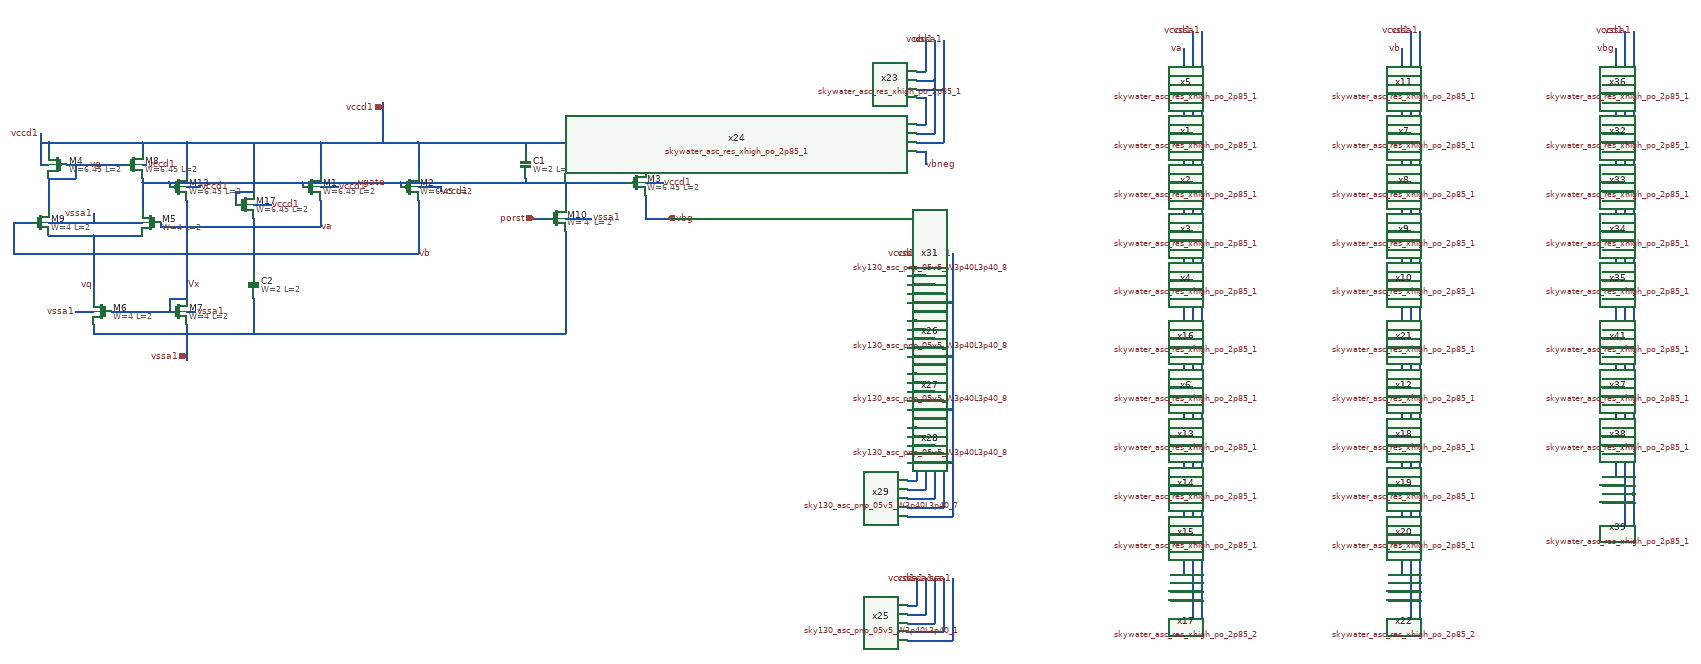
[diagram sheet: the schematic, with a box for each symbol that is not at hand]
v {xschem version=3.0.0 file_version=1.2 }
G {}
K {}
V {}
S {}
E {}
N 2040 520 2260 520 { lab=vccd1}
N 2260 520 2460 520 { lab=vccd1}
N 1430 600 1490 600 { lab=vg}
N 1490 570 1490 600 { lab=vg}
N 1470 570 1490 570 { lab=vg}
N 1490 570 1600 570 { lab=vg}
N 1430 520 1430 540 { lab=vccd1}
N 1430 600 1430 670 { lab=vg}
N 1640 610 1640 670 { lab=vgate}
N 1630 730 1640 730 { lab=vq}
N 1640 570 1650 570 { lab=vccd1}
N 1420 570 1430 570 { lab=vccd1}
N 1430 700 1440 700 { lab=vssa1}
N 1630 700 1640 700 { lab=vssa1}
N 1520 900 1530 900 { lab=vssa1}
N 1570 900 1700 900 { lab=Vx}
N 1740 900 1750 900 { lab=vssa1}
N 1700 870 1700 900 { lab=Vx}
N 1700 870 1740 870 { lab=Vx}
N 2650 520 2770 520 { lab=vccd1}
N 2260 520 2260 590 { lab=vccd1}
N 2770 610 2780 610 { lab=vccd1}
N 2220 610 2220 620 { lab=vgate}
N 2000 610 2000 620 { lab=vgate}
N 1740 620 1750 620 { lab=vccd1}
N 2040 620 2050 620 { lab=vccd1}
N 2040 520 2040 590 { lab=vccd1}
N 2260 620 2270 620 { lab=vccd1}
N 1780 520 2040 520 { lab=vccd1}
N 2700 610 2730 610 { lab=vgate}
N 1700 610 1700 620 { lab=vgate}
N 1740 520 1740 590 { lab=vccd1}
N 1910 710 2040 710 { lab=va}
N 2770 520 2770 580 { lab=vccd1}
N 1430 520 1640 520 { lab=vccd1}
N 1430 730 1440 730 { lab=vq}
N 1530 730 1630 730 { lab=vq}
N 2460 520 2650 520 { lab=vccd1}
N 1740 650 1740 840 { lab=Vx}
N 2000 610 2220 610 { lab=vgate}
N 2220 610 2700 610 { lab=vgate}
N 1440 730 1530 730 { lab=vq}
N 1640 600 1640 610 { lab=vgate}
N 1640 610 1700 610 { lab=vgate}
N 1640 520 1740 520 { lab=vccd1}
N 1440 700 1630 700 { lab=vssa1}
N 1740 520 1780 520 { lab=vccd1}
N 1840 610 2000 610 { lab=vgate}
N 1700 610 1840 610 { lab=vgate}
N 2590 690 2600 690 { lab=vssa1}
N 2590 610 2590 660 { lab=vgate}
N 2500 520 2500 540 { lab=vccd1}
N 2500 600 2500 610 { lab=vgate}
N 1830 710 1910 710 { lab=va}
N 1370 770 2150 770 { lab=#net1}
N 2040 650 2040 710 { lab=va}
N 1680 710 1830 710 { lab=va}
N 1680 700 1680 710 { lab=va}
N 1890 690 1890 710 { lab=va}
N 1850 630 1890 630 { lab=vccd1}
N 1850 630 1850 660 { lab=vccd1}
N 1890 520 1890 630 { lab=vccd1}
N 2770 690 2830 690 { lab=vbg}
N 2150 770 2260 770 { lab=#net1}
N 2180 450 2180 520 { lab=vccd1}
N 2780 610 2810 610 { lab=vccd1}
N 2310 620 2310 630 { lab=vccd1}
N 2270 620 2310 620 { lab=vccd1}
N 2050 620 2080 620 { lab=vccd1}
N 1750 620 1770 620 { lab=vccd1}
N 1640 520 1640 540 { lab=vccd1}
N 1410 570 1420 570 { lab=vccd1}
N 1410 500 1410 570 { lab=vccd1}
N 2600 690 2650 690 { lab=vssa1}
N 1890 660 1930 660 { lab=vccd1}
N 2510 690 2550 690 { lab=porst}
N 1750 900 1760 900 { lab=vssa1}
N 1490 900 1520 900 { lab=vssa1}
N 1530 680 1530 700 { lab=vssa1}
N 1350 700 1390 700 { lab=#net1}
N 1350 700 1350 770 { lab=#net1}
N 1350 770 1370 770 { lab=#net1}
N 2180 430 2180 450 { lab=vccd1}
N 3950 430 3980 430 { lab=#net2}
N 3980 430 3980 480 { lab=#net2}
N 3950 480 3980 480 { lab=#net2}
N 3950 540 3980 540 { lab=#net3}
N 3980 540 3980 590 { lab=#net3}
N 3950 590 3980 590 { lab=#net3}
N 3950 650 3980 650 { lab=#net4}
N 3980 650 3980 700 { lab=#net4}
N 3950 700 3980 700 { lab=#net4}
N 3950 760 3980 760 { lab=#net5}
N 3980 760 3980 810 { lab=#net5}
N 3950 810 3980 810 { lab=#net5}
N 3950 870 3980 870 { lab=#net6}
N 3980 870 3980 920 { lab=#net6}
N 3950 1000 3980 1000 { lab=#net7}
N 3980 1000 3980 1050 { lab=#net7}
N 3950 1050 3980 1050 { lab=#net7}
N 3950 1110 3980 1110 { lab=#net8}
N 3980 1110 3980 1160 { lab=#net8}
N 3950 1160 3980 1160 { lab=#net8}
N 3950 1220 3980 1220 { lab=#net9}
N 3980 1220 3980 1270 { lab=#net9}
N 3950 1270 3980 1270 { lab=#net9}
N 3950 1330 3980 1330 { lab=#net10}
N 3980 1330 3980 1380 { lab=#net10}
N 3950 1380 3980 1380 { lab=#net10}
N 3950 1440 3980 1440 { lab=#net11}
N 3950 940 3980 940 { lab=#net6}
N 3980 920 3980 940 { lab=#net6}
N 3950 1490 3980 1490 { lab=#net11}
N 3980 1440 3980 1490 { lab=#net11}
N 3950 370 3980 370 { lab=va}
N 3980 310 3980 370 { lab=va}
N 3950 390 4000 390 { lab=vccd1}
N 4000 390 4000 1510 { lab=vccd1}
N 3950 1510 4000 1510 { lab=vccd1}
N 3950 500 4000 500 { lab=vccd1}
N 3950 610 4000 610 { lab=vccd1}
N 3950 720 4000 720 { lab=vccd1}
N 3950 830 4000 830 { lab=vccd1}
N 3950 960 4000 960 { lab=vccd1}
N 3950 1070 4000 1070 { lab=vccd1}
N 3950 1180 4000 1180 { lab=vccd1}
N 3950 1290 4000 1290 { lab=vccd1}
N 3950 1400 4000 1400 { lab=vccd1}
N 4000 310 4000 390 { lab=vccd1}
N 4020 310 4020 1590 { lab=vssa1}
N 4000 1510 4000 1590 { lab=vccd1}
N 3950 1420 4020 1420 { lab=vssa1}
N 3950 1310 4020 1310 { lab=vssa1}
N 3950 1200 4020 1200 { lab=vssa1}
N 3950 980 4020 980 { lab=vssa1}
N 3950 850 4020 850 { lab=vssa1}
N 3950 740 4020 740 { lab=vssa1}
N 3950 630 4020 630 { lab=vssa1}
N 3950 520 4020 520 { lab=vssa1}
N 3950 410 4020 410 { lab=vssa1}
N 4000 270 4000 310 { lab=vccd1}
N 3950 1550 4020 1550 { lab=vssa1}
N 4020 270 4020 310 { lab=vssa1}
N 4440 430 4470 430 { lab=#net12}
N 4470 430 4470 480 { lab=#net12}
N 4440 480 4470 480 { lab=#net12}
N 4440 540 4470 540 { lab=#net13}
N 4470 540 4470 590 { lab=#net13}
N 4440 590 4470 590 { lab=#net13}
N 4440 650 4470 650 { lab=#net14}
N 4470 650 4470 700 { lab=#net14}
N 4440 700 4470 700 { lab=#net14}
N 4440 760 4470 760 { lab=#net15}
N 4470 760 4470 810 { lab=#net15}
N 4440 810 4470 810 { lab=#net15}
N 4440 870 4470 870 { lab=#net16}
N 4470 870 4470 920 { lab=#net16}
N 4440 1000 4470 1000 { lab=#net17}
N 4470 1000 4470 1050 { lab=#net17}
N 4440 1050 4470 1050 { lab=#net17}
N 4440 1110 4470 1110 { lab=#net18}
N 4470 1110 4470 1160 { lab=#net18}
N 4440 1160 4470 1160 { lab=#net18}
N 4440 1220 4470 1220 { lab=#net19}
N 4470 1220 4470 1270 { lab=#net19}
N 4440 1270 4470 1270 { lab=#net19}
N 4440 1330 4470 1330 { lab=#net20}
N 4470 1330 4470 1380 { lab=#net20}
N 4440 1380 4470 1380 { lab=#net20}
N 4440 1440 4470 1440 { lab=#net21}
N 4440 940 4470 940 { lab=#net16}
N 4470 920 4470 940 { lab=#net16}
N 4440 1490 4470 1490 { lab=#net21}
N 4470 1440 4470 1490 { lab=#net21}
N 4440 370 4470 370 { lab=vb}
N 4470 310 4470 370 { lab=vb}
N 4440 390 4490 390 { lab=vccd1}
N 4490 390 4490 1510 { lab=vccd1}
N 4440 1510 4490 1510 { lab=vccd1}
N 4440 500 4490 500 { lab=vccd1}
N 4440 610 4490 610 { lab=vccd1}
N 4440 720 4490 720 { lab=vccd1}
N 4440 830 4490 830 { lab=vccd1}
N 4440 960 4490 960 { lab=vccd1}
N 4440 1070 4490 1070 { lab=vccd1}
N 4440 1180 4490 1180 { lab=vccd1}
N 4440 1290 4490 1290 { lab=vccd1}
N 4440 1400 4490 1400 { lab=vccd1}
N 4490 310 4490 390 { lab=vccd1}
N 4510 310 4510 1590 { lab=vssa1}
N 4490 1510 4490 1590 { lab=vccd1}
N 4440 1420 4510 1420 { lab=vssa1}
N 4440 1310 4510 1310 { lab=vssa1}
N 4440 1200 4510 1200 { lab=vssa1}
N 4440 980 4510 980 { lab=vssa1}
N 4440 850 4510 850 { lab=vssa1}
N 4440 740 4510 740 { lab=vssa1}
N 4440 630 4510 630 { lab=vssa1}
N 4440 520 4510 520 { lab=vssa1}
N 4440 410 4510 410 { lab=vssa1}
N 4490 270 4490 310 { lab=vccd1}
N 4440 1550 4510 1550 { lab=vssa1}
N 4510 270 4510 310 { lab=vssa1}
N 4920 430 4950 430 { lab=#net22}
N 4950 430 4950 480 { lab=#net22}
N 4920 480 4950 480 { lab=#net22}
N 4920 540 4950 540 { lab=#net23}
N 4950 540 4950 590 { lab=#net23}
N 4920 590 4950 590 { lab=#net23}
N 4920 650 4950 650 { lab=#net24}
N 4950 650 4950 700 { lab=#net24}
N 4920 700 4950 700 { lab=#net24}
N 4920 760 4950 760 { lab=#net25}
N 4950 760 4950 810 { lab=#net25}
N 4920 810 4950 810 { lab=#net25}
N 4920 870 4950 870 { lab=#net26}
N 4950 870 4950 920 { lab=#net26}
N 4920 1000 4950 1000 { lab=#net27}
N 4950 1000 4950 1050 { lab=#net27}
N 4920 1050 4950 1050 { lab=#net27}
N 4920 1110 4950 1110 { lab=#net28}
N 4950 1110 4950 1160 { lab=#net28}
N 4920 1160 4950 1160 { lab=#net28}
N 4920 1220 4950 1220 { lab=#net29}
N 4950 1220 4950 1270 { lab=#net29}
N 4920 1270 4950 1270 { lab=#net29}
N 4920 1330 4950 1330 { lab=vssa1}
N 4920 940 4950 940 { lab=#net26}
N 4950 920 4950 940 { lab=#net26}
N 4920 370 4950 370 { lab=vbg}
N 4950 310 4950 370 { lab=vbg}
N 4920 390 4970 390 { lab=vccd1}
N 4920 500 4970 500 { lab=vccd1}
N 4920 610 4970 610 { lab=vccd1}
N 4920 720 4970 720 { lab=vccd1}
N 4920 830 4970 830 { lab=vccd1}
N 4920 960 4970 960 { lab=vccd1}
N 4920 1070 4970 1070 { lab=vccd1}
N 4920 1180 4970 1180 { lab=vccd1}
N 4920 1290 4970 1290 { lab=vccd1}
N 4970 310 4970 390 { lab=vccd1}
N 4920 1310 4990 1310 { lab=vssa1}
N 4920 1200 4990 1200 { lab=vssa1}
N 4920 980 4990 980 { lab=vssa1}
N 4920 850 4990 850 { lab=vssa1}
N 4920 740 4990 740 { lab=vssa1}
N 4920 630 4990 630 { lab=vssa1}
N 4920 520 4990 520 { lab=vssa1}
N 4920 410 4990 410 { lab=vssa1}
N 4970 270 4970 310 { lab=vccd1}
N 4990 270 4990 310 { lab=vssa1}
N 4990 310 4990 1310 { lab=vssa1}
N 4970 390 4970 1380 { lab=vccd1}
N 4990 1310 4990 1380 { lab=vssa1}
N 4950 1330 4990 1330 { lab=vssa1}
N 2770 640 2770 690 { lab=vbg}
N 3380 420 3400 420 { lab=#net30}
N 3400 420 3400 480 { lab=#net30}
N 3380 480 3400 480 { lab=#net30}
N 3400 290 3400 360 { lab=vb}
N 3380 360 3400 360 { lab=vb}
N 3400 540 3400 570 { lab=vbneg}
N 3380 540 3400 540 { lab=vbneg}
N 3380 380 3420 380 { lab=vccd1}
N 3420 380 3420 500 { lab=vccd1}
N 3380 500 3420 500 { lab=vccd1}
N 3380 520 3440 520 { lab=vssa1}
N 3440 400 3440 520 { lab=vssa1}
N 3380 400 3440 400 { lab=vssa1}
N 3420 290 3420 380 { lab=vccd1}
N 3440 290 3440 400 { lab=vssa1}
N 2260 650 2260 740 { lab=#net1}
N 3380 770 3380 1280 { lab=vccd1}
N 3360 1280 3380 1280 { lab=vccd1}
N 3400 770 3400 1300 { lab=vssa1}
N 3360 1300 3400 1300 { lab=vssa1}
N 3420 770 3420 1320 { lab=vssa1}
N 3360 1320 3420 1320 { lab=vssa1}
N 3440 770 3440 1340 { lab=vbneg}
N 3360 1340 3440 1340 { lab=vbneg}
N 3460 770 3460 1360 { lab=vssa1}
N 3360 1360 3460 1360 { lab=vssa1}
N 3360 800 3380 800 { lab=vccd1}
N 3360 820 3400 820 { lab=vssa1}
N 3360 840 3420 840 { lab=vssa1}
N 3360 860 3440 860 { lab=vbneg}
N 3360 880 3460 880 { lab=vssa1}
N 3360 920 3380 920 { lab=vccd1}
N 3360 940 3400 940 { lab=vssa1}
N 3360 960 3420 960 { lab=vssa1}
N 3360 980 3440 980 { lab=vbneg}
N 3360 1000 3460 1000 { lab=vssa1}
N 3360 1040 3380 1040 { lab=vccd1}
N 3360 1060 3400 1060 { lab=vssa1}
N 3360 1080 3420 1080 { lab=vssa1}
N 3360 1100 3440 1100 { lab=vbneg}
N 3360 1120 3460 1120 { lab=vssa1}
N 3360 1160 3380 1160 { lab=vccd1}
N 3360 1180 3400 1180 { lab=vssa1}
N 3360 1200 3420 1200 { lab=vssa1}
N 3360 1220 3440 1220 { lab=vbneg}
N 3360 1240 3460 1240 { lab=vssa1}
N 1740 950 1740 1010 { lab=vssa1}
N 3360 1620 3440 1620 { lab=va}
N 3440 1500 3440 1620 { lab=va}
N 3380 1500 3380 1560 { lab=vccd1}
N 3360 1560 3380 1560 { lab=vccd1}
N 3400 1500 3400 1580 { lab=vssa1}
N 3360 1580 3400 1580 { lab=vssa1}
N 3420 1500 3420 1600 { lab=vssa1}
N 3360 1600 3420 1600 { lab=vssa1}
N 3460 1500 3460 1640 { lab=vssa1}
N 3360 1640 3460 1640 { lab=vssa1}
N 1740 840 1740 870 { lab=Vx}
N 1530 930 1530 950 { lab=vssa1}
N 1530 950 1740 950 { lab=vssa1}
N 1740 930 1740 950 { lab=vssa1}
N 1530 730 1530 870 { lab=vq}
N 2590 720 2590 950 { lab=vssa1}
N 1740 950 2590 950 { lab=vssa1}
N 1890 710 1890 810 { lab=va}
N 1890 870 1890 950 { lab=vssa1}
N 2260 740 2260 770 { lab=#net1}
N 3950 1090 4020 1090 { lab=vssa1}
N 4440 1090 4510 1090 { lab=vssa1}
N 4920 1090 4990 1090 { lab=vssa1}
N 3950 1530 4020 1530 { lab=vssa1}
N 4440 1530 4510 1530 { lab=vssa1}
N 1410 520 1430 520 { lab=vccd1}
C {devices/lab_wire.sym} 2190 610 0 0 {name=l11 lab=vgate}
C {sky130_fd_pr/nfet_01v8_lvt.sym} 1660 700 0 1 {name=M5
L=2
W=4
nf=1
mult=9
ad="'int((nf+1)/2) * W/nf * 0.29'" 
pd="'2*int((nf+1)/2) * (W/nf + 0.29)'"
as="'int((nf+2)/2) * W/nf * 0.29'" 
ps="'2*int((nf+2)/2) * (W/nf + 0.29)'"
nrd="'0.29 / W'" nrs="'0.29 / W'"
sa=0 sb=0 sd=0
model=nfet_01v8_lvt
spiceprefix=X
}
C {sky130_fd_pr/nfet_01v8_lvt.sym} 1550 900 0 1 {name=M6
L=2
W=4
nf=1
mult=1
ad="'int((nf+1)/2) * W/nf * 0.29'" 
pd="'2*int((nf+1)/2) * (W/nf + 0.29)'"
as="'int((nf+2)/2) * W/nf * 0.29'" 
ps="'2*int((nf+2)/2) * (W/nf + 0.29)'"
nrd="'0.29 / W'" nrs="'0.29 / W'"
sa=0 sb=0 sd=0
model=nfet_01v8_lvt
spiceprefix=X
}
C {sky130_fd_pr/nfet_01v8_lvt.sym} 1410 700 0 0 {name=M9
L=2
W=4
nf=1
mult=9
ad="'int((nf+1)/2) * W/nf * 0.29'" 
pd="'2*int((nf+1)/2) * (W/nf + 0.29)'"
as="'int((nf+2)/2) * W/nf * 0.29'" 
ps="'2*int((nf+2)/2) * (W/nf + 0.29)'"
nrd="'0.29 / W'" nrs="'0.29 / W'"
sa=0 sb=0 sd=0
model=nfet_01v8_lvt
spiceprefix=X
}
C {devices/lab_pin.sym} 1550 570 1 0 {name=l2 lab=vg}
C {devices/lab_pin.sym} 1740 840 2 0 {name=l12 lab=Vx}
C {devices/lab_pin.sym} 1530 840 0 0 {name=l18 lab=vq}
C {sky130_fd_pr/nfet_01v8_lvt.sym} 1720 900 0 0 {name=M7
L=2
W=4
nf=1
mult=1
ad="'int((nf+1)/2) * W/nf * 0.29'" 
pd="'2*int((nf+1)/2) * (W/nf + 0.29)'"
as="'int((nf+2)/2) * W/nf * 0.29'" 
ps="'2*int((nf+2)/2) * (W/nf + 0.29)'"
nrd="'0.29 / W'" nrs="'0.29 / W'"
sa=0 sb=0 sd=0
model=nfet_01v8_lvt
spiceprefix=X
}
C {sky130_fd_pr/pfet_01v8_lvt.sym} 1720 620 0 0 {name=M13
L=2
W=6.45
nf=1
mult=12
ad="'int((nf+1)/2) * W/nf * 0.29'" 
pd="'2*int((nf+1)/2) * (W/nf + 0.29)'"
as="'int((nf+2)/2) * W/nf * 0.29'" 
ps="'2*int((nf+2)/2) * (W/nf + 0.29)'"
nrd="'0.29 / W'" nrs="'0.29 / W'"
sa=0 sb=0 sd=0
model=pfet_01v8_lvt
spiceprefix=X
}
C {sky130_fd_pr/pfet_01v8_lvt.sym} 2020 620 0 0 {name=M1
L=2
W=6.45
nf=1
mult=60
ad="'int((nf+1)/2) * W/nf * 0.29'" 
pd="'2*int((nf+1)/2) * (W/nf + 0.29)'"
as="'int((nf+2)/2) * W/nf * 0.29'" 
ps="'2*int((nf+2)/2) * (W/nf + 0.29)'"
nrd="'0.29 / W'" nrs="'0.29 / W'"
sa=0 sb=0 sd=0
model=pfet_01v8_lvt
spiceprefix=X
}
C {sky130_fd_pr/pfet_01v8_lvt.sym} 2240 620 0 0 {name=M2
L=2
W=6.45
nf=1
mult=60
ad="'int((nf+1)/2) * W/nf * 0.29'" 
pd="'2*int((nf+1)/2) * (W/nf + 0.29)'"
as="'int((nf+2)/2) * W/nf * 0.29'" 
ps="'2*int((nf+2)/2) * (W/nf + 0.29)'"
nrd="'0.29 / W'" nrs="'0.29 / W'"
sa=0 sb=0 sd=0
model=pfet_01v8_lvt
spiceprefix=X
}
C {sky130_fd_pr/pfet_01v8_lvt.sym} 2750 610 0 0 {name=M3
L=2
W=6.45
nf=1
mult=60
ad="'int((nf+1)/2) * W/nf * 0.29'" 
pd="'2*int((nf+1)/2) * (W/nf + 0.29)'"
as="'int((nf+2)/2) * W/nf * 0.29'" 
ps="'2*int((nf+2)/2) * (W/nf + 0.29)'"
nrd="'0.29 / W'" nrs="'0.29 / W'"
sa=0 sb=0 sd=0
model=pfet_01v8_lvt
spiceprefix=X
}
C {sky130_fd_pr/pfet_01v8_lvt.sym} 1450 570 0 1 {name=M4
L=2
W=6.45
nf=1
mult=6
ad="'int((nf+1)/2) * W/nf * 0.29'" 
pd="'2*int((nf+1)/2) * (W/nf + 0.29)'"
as="'int((nf+2)/2) * W/nf * 0.29'" 
ps="'2*int((nf+2)/2) * (W/nf + 0.29)'"
nrd="'0.29 / W'" nrs="'0.29 / W'"
sa=0 sb=0 sd=0
model=pfet_01v8_lvt
spiceprefix=X
}
C {sky130_fd_pr/pfet_01v8_lvt.sym} 1620 570 0 0 {name=M8
L=2
W=6.45
nf=1
mult=6
ad="'int((nf+1)/2) * W/nf * 0.29'" 
pd="'2*int((nf+1)/2) * (W/nf + 0.29)'"
as="'int((nf+2)/2) * W/nf * 0.29'" 
ps="'2*int((nf+2)/2) * (W/nf + 0.29)'"
nrd="'0.29 / W'" nrs="'0.29 / W'"
sa=0 sb=0 sd=0
model=pfet_01v8_lvt
spiceprefix=X
}
C {sky130_fd_pr/nfet_01v8_lvt.sym} 2570 690 0 0 {name=M10
L='2'
W='4'
nf=1
mult=9
ad="'int((nf+1)/2) * W/nf * 0.29'" 
pd="'2*int((nf+1)/2) * (W/nf + 0.29)'"
as="'int((nf+2)/2) * W/nf * 0.29'" 
ps="'2*int((nf+2)/2) * (W/nf + 0.29)'"
nrd="'0.29 / W'" nrs="'0.29 / W'"
sa=0 sb=0 sd=0
model=nfet_01v8_lvt
spiceprefix=X
}
C {sky130_fd_pr/pfet_01v8_lvt.sym} 1870 660 0 0 {name=M17
L=2
W=6.45
nf=1
mult=12
ad="'int((nf+1)/2) * W/nf * 0.29'" 
pd="'2*int((nf+1)/2) * (W/nf + 0.29)'"
as="'int((nf+2)/2) * W/nf * 0.29'" 
ps="'2*int((nf+2)/2) * (W/nf + 0.29)'"
nrd="'0.29 / W'" nrs="'0.29 / W'"
sa=0 sb=0 sd=0
model=pfet_01v8_lvt
spiceprefix=X
}
C {devices/ipin.sym} 2520 690 0 0 {name=p1 lab=porst}
C {devices/opin.sym} 2820 690 0 0 {name=p2 lab=vbg}
C {sky130_fd_pr/cap_mim_m3_1.sym} 2500 570 2 0 {name=C1 model=cap_mim_m3_1 W=2 L=2 MF=100 spiceprefix=X}
C {sky130_fd_pr/cap_mim_m3_1.sym} 1890 840 2 0 {name=C2 model=cap_mim_m3_1 W=2 L=2 MF=100 spiceprefix=X}
C {devices/ipin.sym} 2180 440 1 0 {name=p5 lab=vccd1}
C {devices/ipin.sym} 1740 1000 3 0 {name=p6 lab=vssa1}
C {devices/lab_pin.sym} 2810 610 2 0 {name=l1 sig_type=std_logic lab=vccd1}
C {devices/lab_pin.sym} 2310 630 2 0 {name=l3 sig_type=std_logic lab=vccd1}
C {devices/lab_pin.sym} 2080 620 2 0 {name=l5 sig_type=std_logic lab=vccd1}
C {devices/lab_pin.sym} 1770 620 2 0 {name=l6 sig_type=std_logic lab=vccd1}
C {devices/lab_pin.sym} 1650 570 2 0 {name=l7 sig_type=std_logic lab=vccd1}
C {devices/lab_pin.sym} 1410 500 1 0 {name=l8 sig_type=std_logic lab=vccd1}
C {devices/lab_pin.sym} 2650 690 2 0 {name=l9 sig_type=std_logic lab=vssa1}
C {devices/lab_pin.sym} 1930 660 2 0 {name=l13 sig_type=std_logic lab=vccd1}
C {devices/lab_pin.sym} 1760 900 2 0 {name=l16 sig_type=std_logic lab=vssa1}
C {devices/lab_pin.sym} 1490 900 0 0 {name=l17 sig_type=std_logic lab=vssa1}
C {devices/lab_pin.sym} 1530 680 1 0 {name=l19 sig_type=std_logic lab=vssa1}
C {analog_stdcells/skywater_asc_res_xhigh_po_2p85_1.sym} 3800 510 0 0 {name=x1}
C {analog_stdcells/skywater_asc_res_xhigh_po_2p85_1.sym} 3800 620 0 0 {name=x2}
C {analog_stdcells/skywater_asc_res_xhigh_po_2p85_1.sym} 3800 730 0 0 {name=x3}
C {analog_stdcells/skywater_asc_res_xhigh_po_2p85_1.sym} 3800 840 0 0 {name=x4}
C {analog_stdcells/skywater_asc_res_xhigh_po_2p85_1.sym} 3800 400 0 0 {name=x5}
C {analog_stdcells/skywater_asc_res_xhigh_po_2p85_1.sym} 3800 1080 0 0 {name=x6}
C {analog_stdcells/skywater_asc_res_xhigh_po_2p85_1.sym} 3800 1190 0 0 {name=x13}
C {analog_stdcells/skywater_asc_res_xhigh_po_2p85_1.sym} 3800 1300 0 0 {name=x14}
C {analog_stdcells/skywater_asc_res_xhigh_po_2p85_1.sym} 3800 1410 0 0 {name=x15}
C {analog_stdcells/skywater_asc_res_xhigh_po_2p85_1.sym} 3800 970 0 0 {name=x16}
C {devices/lab_pin.sym} 3980 310 1 0 {name=l20 sig_type=std_logic lab=va
}
C {devices/lab_pin.sym} 4000 270 1 0 {name=l22 sig_type=std_logic lab=vccd1

}
C {devices/lab_pin.sym} 4020 270 1 0 {name=l23 sig_type=std_logic lab=vssa1


}
C {analog_stdcells/skywater_asc_res_xhigh_po_2p85_1.sym} 4290 510 0 0 {name=x7}
C {analog_stdcells/skywater_asc_res_xhigh_po_2p85_1.sym} 4290 620 0 0 {name=x8}
C {analog_stdcells/skywater_asc_res_xhigh_po_2p85_1.sym} 4290 730 0 0 {name=x9}
C {analog_stdcells/skywater_asc_res_xhigh_po_2p85_1.sym} 4290 840 0 0 {name=x10}
C {analog_stdcells/skywater_asc_res_xhigh_po_2p85_1.sym} 4290 400 0 0 {name=x11}
C {analog_stdcells/skywater_asc_res_xhigh_po_2p85_1.sym} 4290 1080 0 0 {name=x12}
C {analog_stdcells/skywater_asc_res_xhigh_po_2p85_1.sym} 4290 1190 0 0 {name=x18}
C {analog_stdcells/skywater_asc_res_xhigh_po_2p85_1.sym} 4290 1300 0 0 {name=x19}
C {analog_stdcells/skywater_asc_res_xhigh_po_2p85_1.sym} 4290 1410 0 0 {name=x20}
C {analog_stdcells/skywater_asc_res_xhigh_po_2p85_1.sym} 4290 970 0 0 {name=x21}
C {devices/lab_pin.sym} 4470 310 1 0 {name=l21 sig_type=std_logic lab=vb
}
C {devices/lab_pin.sym} 4490 270 1 0 {name=l24 sig_type=std_logic lab=vccd1

}
C {devices/lab_pin.sym} 4510 270 1 0 {name=l25 sig_type=std_logic lab=vssa1


}
C {analog_stdcells/skywater_asc_res_xhigh_po_2p85_1.sym} 4770 510 0 0 {name=x32}
C {analog_stdcells/skywater_asc_res_xhigh_po_2p85_1.sym} 4770 620 0 0 {name=x33}
C {analog_stdcells/skywater_asc_res_xhigh_po_2p85_1.sym} 4770 730 0 0 {name=x34}
C {analog_stdcells/skywater_asc_res_xhigh_po_2p85_1.sym} 4770 840 0 0 {name=x35}
C {analog_stdcells/skywater_asc_res_xhigh_po_2p85_1.sym} 4770 400 0 0 {name=x36}
C {analog_stdcells/skywater_asc_res_xhigh_po_2p85_1.sym} 4770 1080 0 0 {name=x37}
C {analog_stdcells/skywater_asc_res_xhigh_po_2p85_1.sym} 4770 1190 0 0 {name=x38}
C {analog_stdcells/skywater_asc_res_xhigh_po_2p85_1.sym} 4770 1300 0 0 {name=x39}
C {analog_stdcells/skywater_asc_res_xhigh_po_2p85_1.sym} 4770 970 0 0 {name=x41}
C {devices/lab_pin.sym} 4950 310 1 0 {name=l26 sig_type=std_logic lab=vbg

}
C {devices/lab_pin.sym} 4970 270 1 0 {name=l27 sig_type=std_logic lab=vccd1

}
C {devices/lab_pin.sym} 4990 270 1 0 {name=l28 sig_type=std_logic lab=vssa1


}
C {analog_stdcells/skywater_asc_res_xhigh_po_2p85_1.sym} 3230 390 0 0 {name=x23}
C {analog_stdcells/skywater_asc_res_xhigh_po_2p85_1.sym} 3230 510 0 0 {name=x24}
C {devices/lab_pin.sym} 3400 290 1 0 {name=l10 sig_type=std_logic lab=vb
}
C {devices/lab_pin.sym} 3400 570 2 0 {name=l29 lab=vbneg}
C {devices/lab_pin.sym} 3420 290 1 0 {name=l30 sig_type=std_logic lab=vccd1

}
C {devices/lab_pin.sym} 3440 290 1 0 {name=l31 sig_type=std_logic lab=vssa1


}
C {devices/lab_pin.sym} 3380 770 1 0 {name=l15 sig_type=std_logic lab=vccd1

}
C {devices/lab_pin.sym} 3400 770 1 0 {name=l32 sig_type=std_logic lab=vssa1


}
C {devices/lab_pin.sym} 3420 770 1 0 {name=l33 sig_type=std_logic lab=vssa1


}
C {devices/lab_pin.sym} 3440 770 1 0 {name=l34 lab=vbneg}
C {devices/lab_pin.sym} 3460 770 1 0 {name=l35 sig_type=std_logic lab=vssa1


}
C {devices/lab_pin.sym} 3440 1500 1 0 {name=l4 sig_type=std_logic lab=va
}
C {devices/lab_pin.sym} 3380 1500 1 0 {name=l14 sig_type=std_logic lab=vccd1

}
C {devices/lab_pin.sym} 3400 1500 1 0 {name=l36 sig_type=std_logic lab=vssa1


}
C {devices/lab_pin.sym} 3420 1500 1 0 {name=l37 sig_type=std_logic lab=vssa1


}
C {devices/lab_pin.sym} 3460 1500 1 0 {name=l38 sig_type=std_logic lab=vssa1


}
C {xschem/skywater_asc_res_xhigh_po_2p85_2.sym} 3800 1520 0 0 {name=x17}
C {xschem/skywater_asc_res_xhigh_po_2p85_2.sym} 4290 1520 0 0 {name=x22}
C {xschem/sky130_asc_pnp_05v5_W3p40L3p40_8.sym} 3210 840 0 0 {name=x31}
C {xschem/sky130_asc_pnp_05v5_W3p40L3p40_8.sym} 3210 960 0 0 {name=x26}
C {xschem/sky130_asc_pnp_05v5_W3p40L3p40_8.sym} 3210 1080 0 0 {name=x27}
C {xschem/sky130_asc_pnp_05v5_W3p40L3p40_8.sym} 3210 1200 0 0 {name=x28}
C {xschem/sky130_asc_pnp_05v5_W3p40L3p40_7.sym} 3210 1320 0 0 {name=x29}
C {xschem/sky130_asc_pnp_05v5_W3p40L3p40_1.sym} 3210 1600 0 0 {name=x25}
C {devices/lab_pin.sym} 2040 710 2 0 {name=l39 sig_type=std_logic lab=va
}
C {devices/lab_pin.sym} 2260 770 2 0 {name=l40 sig_type=std_logic lab=vb
}
